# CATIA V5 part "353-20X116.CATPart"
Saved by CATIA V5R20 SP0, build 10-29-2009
Part number: 353-20X116
Definition: NONE
Nomenclature: 353-20X116
Source: Unknown
Description: 353-20X116
Bounding box of the stored display mesh (mm): x -6 to 110, y -16 to 16, z -16 to 16
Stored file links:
  C:\Users\Utente\Desktop\IO LAVORO\3D X SITO CF\X SITO\PLASTICA\353\353-20X116.CATPart

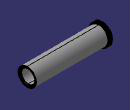
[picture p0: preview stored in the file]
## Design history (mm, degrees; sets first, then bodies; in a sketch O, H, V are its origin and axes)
Body1 "353-20X116" (main body)
  Solid1: solid without history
